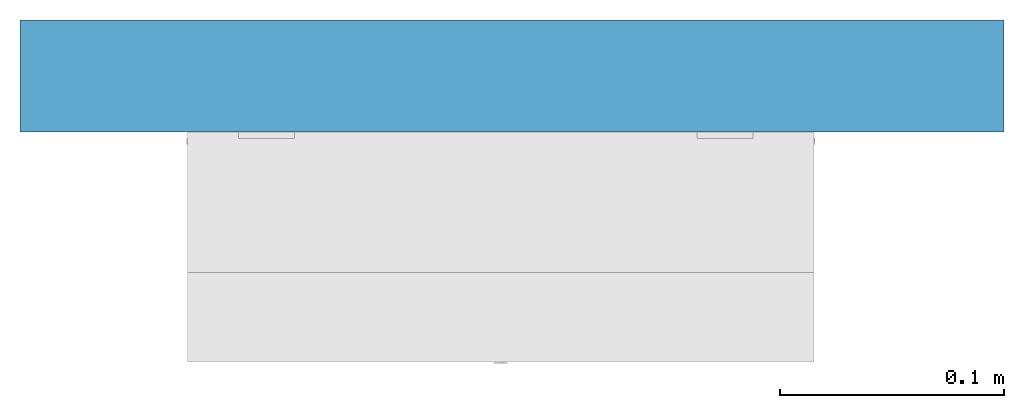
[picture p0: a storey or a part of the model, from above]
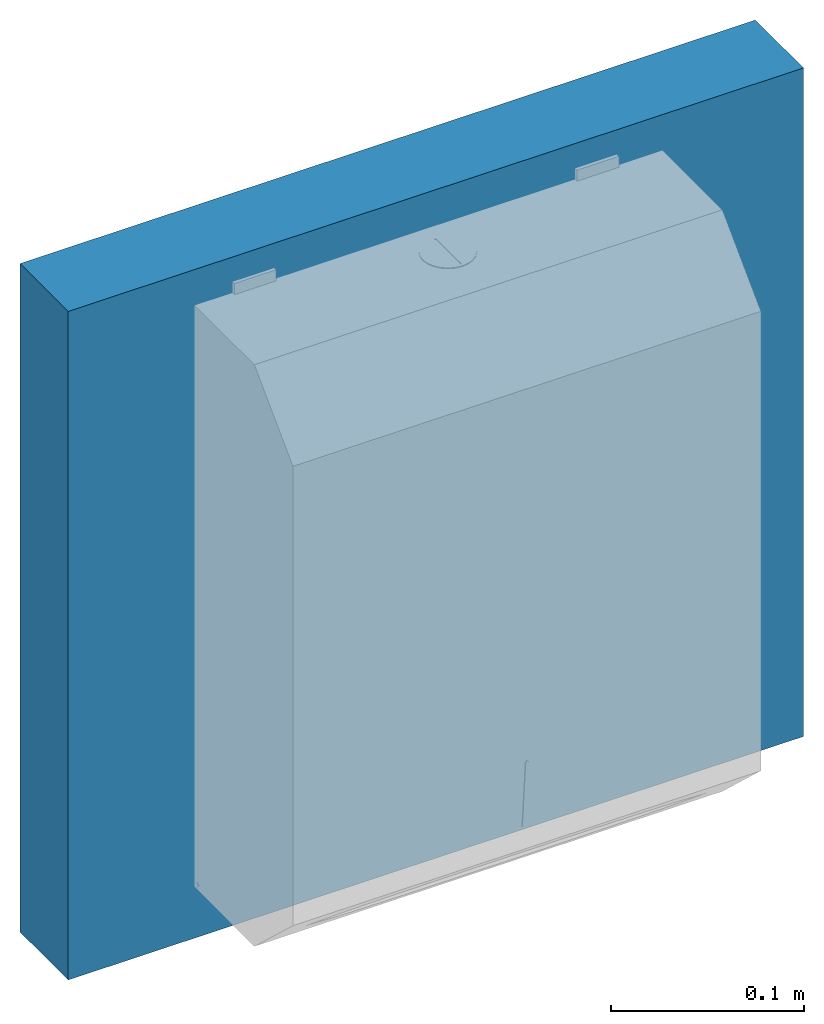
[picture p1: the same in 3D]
Properties of the parts of a building model (IFC2X3)

# File
Description: ViewDefinition [CoordinationView]
Time: 2016-12-21T09:51:16
Written by: The EXPRESS Data Manager Version 5.01.0100.02.64mod : 6 Jun 2012
Made in: 20140709_2115(x64) - Exporter 2014.0.2014.0709 - Default UI
Comment: STEP Physical File produced by: The EXPRESS Data Manager Version 5.01.0100.02.64mod : 6 Jun 2012 * Module: EDMstepFileFactory/EDMstandAlone * Creation date: Wed Dec 21 09:51:16 2016 * Host: BIM-HP * Database: C:\Users\dcole\AppData\Local\Temp\{48DB1A7A-29DC-4D5C-84D8-656DB22B0ED8}\ifc * Database version: 5507 * Database creation date: Wed Dec 21 09:51:14 2016 * Schema: IFC2X3 * Model: DataRepository.ifc * Model creation date: Wed Dec 21 09:51:14 2016 * Header model: DataRepository.ifc_HeaderModel * Header model creation date: Wed Dec 21 09:51:14 2016 * EDMuser: sdai-user * EDMgroup: sdai-group * License ID and type: 5605 : Permanent license. Expiry date: * EDMstepFileFactory options: 020000

# IfcProject
LongName: P:\Fastrack\53721_BELL-CHEM\ADDITIONAL DRAWINGS 2016 BIM\IFC\BC928.ifc

# IfcSite, Default
RefLatitude: 42, 24, 53, 508911; RefLongitude: -71, -15, -29, -58837; RefElevation: 0 mm

# IfcBuilding
Pset_BuildingCommon - NumberOfStoreys: 1

# IfcBuildingStorey, Level 1
LongName: Level 1; Elevation: 0 mm
Constraints - Elevation Base: Project Base Point; Elevation: 0 mm
Dimensions - Computation Height: 0 mm
Identity Data - Name: Level 1; Structural: no; Building Story: yes
Graphics - Line Weight: 1; Symbol at End 2 Default: yes; Line Pattern: -3000010; Color: 0; Symbol at End 1 Default: no

# IfcBuildingElementProxy: BC928 Dolphin Stainless Steel Maxi Paper Towel Dispenser, BC928:BC928 Dolphin Stainless Steel Maxi Paper Towel Dispenser:36537
In: Level 1
Material: Stainless Steel, Glass
Constraints - Offset: -147.346 mm; Level: Level: Level 1; Moves With Nearby Elements: no; Host: Level : Level 1
Phasing - Phase Created: New Construction
Dimensions - Volume: 0.0100558 m3; Capacity Paper Towels: 450 C-fold or multi-fold towels; Height: 370mm; Projection: 103mm; Width: 280mm
Pset_ManufacturerTypeInformation - Manufacturer: Dolphin Solutions Ltd.
Pset_BuildingElementProxyCommon - Reference: BC928 Dolphin Stainless Steel Maxi Paper Towel Dispenser
Identity Data - URL: www.dolphinsolutions.co.uk; Manufacturer: Dolphin Solutions Ltd.; Fax No.: +44 (0) 1424 205200; Model: BC928; Description: Stainless steel maxi paper towel dispenser; Assembly Description: Misc. Other Plumbing Systems; Assembly Code: D2090900; Type Comments: Same product with polished finish = BC928B; Email: info@dolphinsolutions.co.uk; Tel No.: +44 (0) 1424 202224; Address: Southpoint, Compass Park, Junction Road, Bodiam, TN32 5BS
General - Product Page Link: https://www.dolphinsolutions.co.uk/product/stainless-steel-maxi-paper-towel-dispenser/; Product Data: Lockable paper towel dispenser. High quality stainless steel. Ideal for larger washrooms. Holds 450 C-fold or multi-fold towels

# IfcWallStandardCase: Basic Wall:Wall 1, Basic Wall:Wall 1:3092
In: Level 1
Type - PredefinedType: STANDARD; Material: Default Wall 50 mm
Type - Analytical Properties - Absorptance: 0.1; Roughness: 1
Type - Graphics - Coarse Scale Fill Color: 8454143
Type - Construction - Wrapping at Inserts: Do not wrap; Width: 50 mm; Function: Exterior
Constraints - Unconnected Height: 422.96 mm; Base Offset: -175.506 mm; Top Offset: 0 mm; Base Extension Distance: 0 mm; Base Constraint: Level: Level 1; Base is Attached: no; Related to Mass: no; Location Line: Finish Face: Interior; Top is Attached: no; Top Extension Distance: 0 mm; Room Bounding: yes
Dimensions - Volume: 0.00930512 m3; Area: 0.186102 m2; Length: 440 mm
Phasing - Phase Created: New Construction
Structural - Structural Usage: Non-bearing; Structural: no; Enable Analytical Model: no
Pset_WallCommon - Reference: Wall 1; LoadBearing: no; ExtendToStructure: no; IsExternal: yes
